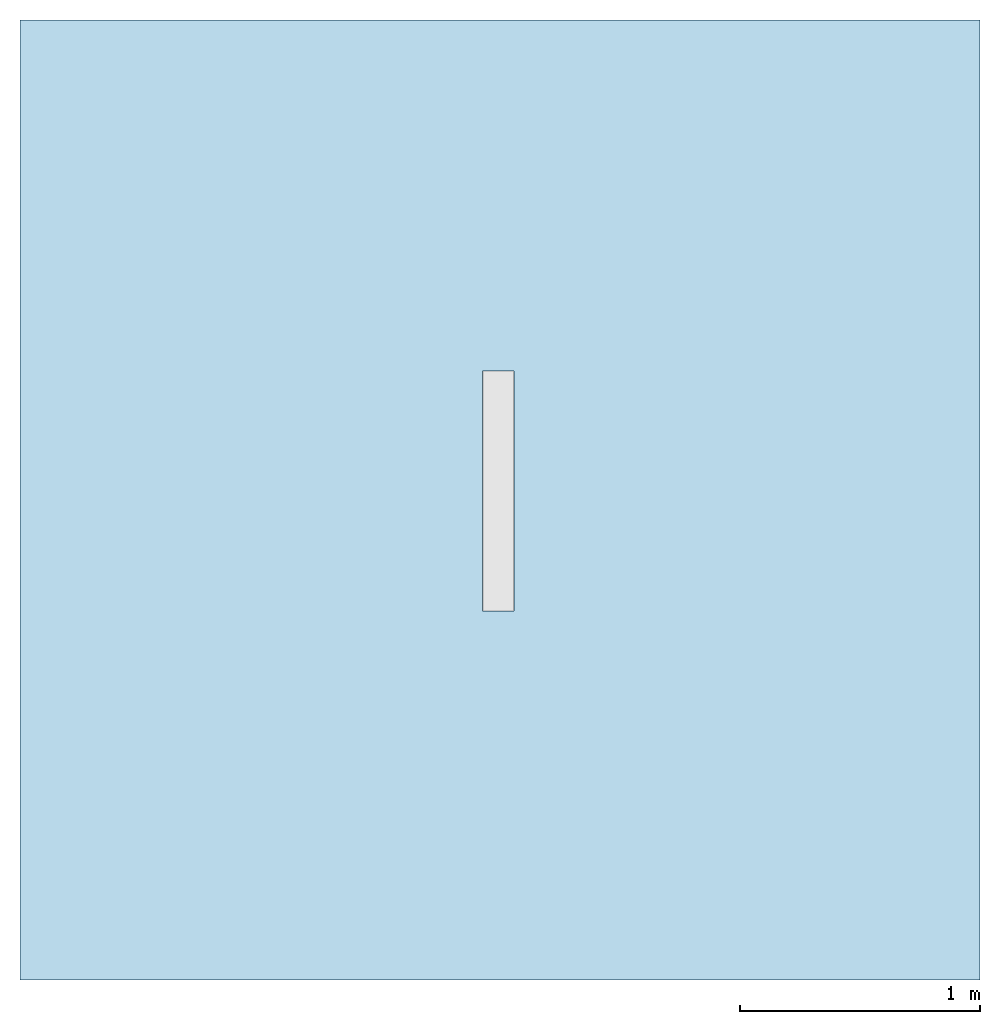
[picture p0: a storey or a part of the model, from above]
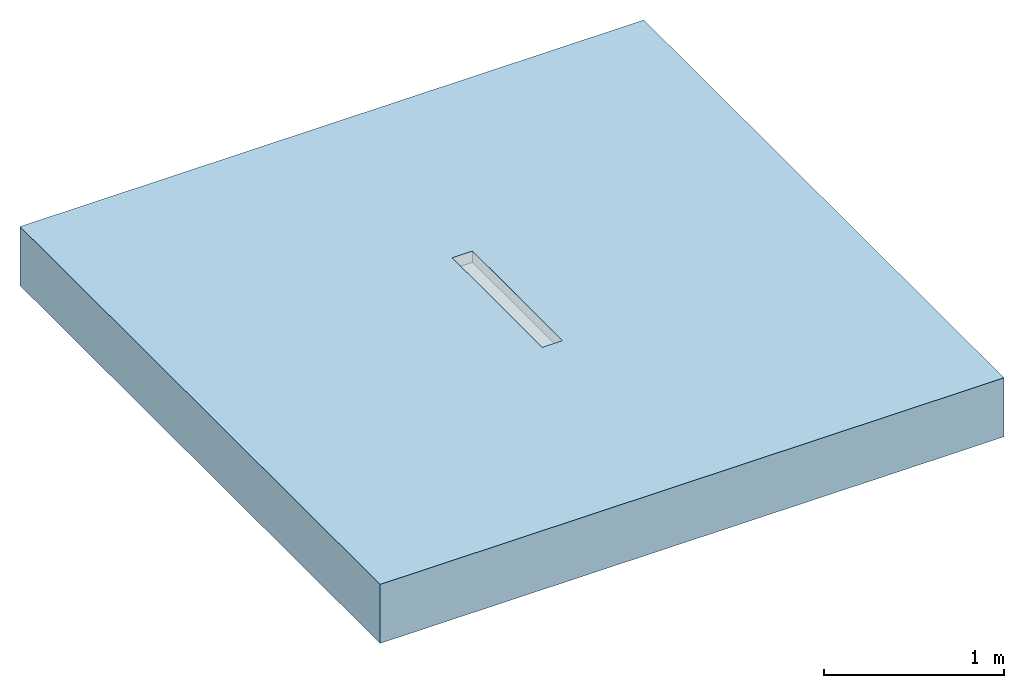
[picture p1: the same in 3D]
Properties of the parts of a building model (IFC2X3)

# File
Description: ViewDefinition [CoordinationView]
File name: Project Number
Time: 2014-06-06T15:01:31
Written by: The EXPRESS Data Manager Version 5.01.0100.02.64mod : 6 Jun 2012
Made in: 20130308_1515(x64) - Exporter 2014.0.2013.0308 - Default UI
Comment: STEP Physical File produced by: The EXPRESS Data Manager Version 5.01.0100.02.64mod : 6 Jun 2012 * Module: EDMstepFileFactory/EDMstandAlone * Creation date: Fri Jun 06 15:01:31 2014 * Host: IN-BLR-PC-0010 * Database: C:\Users\palleri\AppData\Local\Temp\{C48A4689-CF1B-40E8-B13B-AC1FC0C0441A}\ifc * Database version: 5507 * Database creation date: Fri Jun 06 15:01:29 2014 * Schema: IFC2X3 * Model: DataRepository.ifc * Model creation date: Fri Jun 06 15:01:30 2014 * Header model: DataRepository.ifc_HeaderModel * Header model creation date: Fri Jun 06 15:01:30 2014 * EDMuser: sdai-user * EDMgroup: sdai-group * License ID and type: 5605 : Permanent license. Expiry date: * EDMstepFileFactory options: 020000

# IfcProject, Project Number
LongName: Project Name; Phase: Project Status

# IfcSite, Default
RefLatitude: 42, 21, 30, 344238; RefLongitude: -71, -3, -35, -194702; RefElevation: 0 mm

# IfcBuilding
Pset_BuildingCommon - NumberOfStoreys: 1
Other - Client Name: Owner; Project Issue Date: Issue Date; Project Status: Project Status; Project Address: ## Street City, State Zip; Project Name: Project Name; Project Number: Project Number

# IfcBuildingStorey, Level 1
LongName: Level 1; Elevation: 0 mm
Graphics - Line Weight: 1; Line Pattern: Center; Symbol at End 1 Default: no; Symbol at End 2 Default: yes; Color: 0; Symbol: M_Level Head - Circle: M_Level Head - Circle
Constraints - Elevation Base: Project Base Point; Elevation: 0 mm
Identity Data - Name: Level 1; Building Story: yes; Structural: no
Dimensions - Computation Height: 0 mm

# IfcFlowTerminal: 36986 - Fixed Height Channel - Shallow Section - 1000mm LG - Invert Depth 75mm, ACO Freedeck Fixed Height Channel Intermediate Section Stainless Steel:36986 - Fixed Height Channel - Shallow Section - 1000mm LG - Invert Depth 75mm:322678
In: Level 1
Material: Stainless Steel Grade 304
Construction - End Plate Invert 1: no; 36954 - Grating - Plain Mesh - Stainless Steel 304 - 500mm long: no; End Plate Invert 2: no; 00272 - Grating - Slotted Grating - Stainless Steel 304 - 1000mm long: no; 36955 - Grating - Plain Mesh - Stainless Steel 304 - 1000mm long: yes; 00273 - Grating - Slotted Grating - Stainless Steel 304 - 500mm long: no
Phasing - Phase Created: New Construction
Identity Data - Mark: 29; Watermark1: This file is the property of ACO Technologies PLC; Manufacturer: ACO Building Drainage; E-mail Technical: abdtechnical@aco.co.uk; Fax: +44 (0)1462 851490; Watermark2: This file is water marked and users are prohibited to reproduce, adapt, distribute this information; Website: www.acobd.com; Watermarked By: www.acobd.com; Telephone: +44 (0)1462 816666; Watermarked With: BIM Manager Premium Suite; E-mail Sales: abdcommercial@aco.co.uk; Address: ACO Business Centre, Caxton Road, Bedford, MK41 0LF
Constraints - Level: Level: Level 1; Moves With Nearby Elements: no
Pset_ManufacturerTypeInformation - Manufacturer: ACO Building Drainage
General - Product Standard: BS EN 1433:2002, CE marked; Product Range: ACO Freedeck; Channel Recyclable: Fully recyclable; Product Description: ACO FreeDeck Fixed Height Channel - Intermediate Section; NBS Specification: NBS Section R10 Gravity Rainwater Drainage Systems, Subsection 365; Load Class: A15; Product Type: Linear Deck Drainage System; Channel Colour: Mid Grey; Maintenance Guidelines: X:\Electronic Literature\ABD Electronic Literature\Roof and Balcony Drainage\ACO Freedeck Brochure.pdf; Weight (Kg): 2.65kg; Dimensions (LxWxH): 1000 x 130 x 75; Installation Guidelines: X:\Electronic Literature\ABD Electronic Literature\Roof and Balcony Drainage\ACO Freedeck Brochure.pdf; Price: POA - contact ACO; Channel Material: Stainless Steel Grade 304; Channel Recycled Material Content: 60-70%; Product Code: 36986
Model Properties - End Plate Product Code 36988: End Plate - Stainless Steel for Invert Depth - 75mm - 0.07Kg; Grating Product Code 00273: Load Class A15 - Slotted Grating - 10 x 80mm Slot - Stainless Steel 304 - 500mm long - 1.0kg; Grating Product Code 36955: Load Class A15 - Mesh Grating - 14mm x 30mm Mesh - Stainless Steel 304 - 1000mm long - 3.0kg; Grating Product Code 00272: Load Class A15 - Slotted Grating - 10 x 80mm Slot - Stainless Steel 304 - 1000mm long - 2.2kg; Grating Product Code 36954: Load Class A15 - Mesh Grating - 14mm x 30mm Mesh - Stainless Steel 304 - 500mm long - 1.6kg
Other - Side Void: 4; Nos: 32
Dimensions - Channel End Length: -1000 mm; Grating End Length: 1000 mm; Height: 75 mm
Materials and Finishes - Material: Stainless Steel Grade 304

# IfcSlab: Floor:Generic Floor - 400mm, Floor:Generic Floor - 400mm:193825
In: Level 1
PredefinedType: FLOOR; Material: Concrete, Broom Finish 400 mm
Dimensions - Area: 16 m2; Thickness: 400 mm; Perimeter: 16000 mm; Volume: 6.39025 m3
Constraints - Height Offset From Level: 0 mm; Related to Mass: no; Room Bounding: yes; Level: Level: Level 1
Structural - Structural: no; Enable Analytical Model: no
Phasing - Phase Created: New Construction
Pset_SlabCommon - Reference: Generic Floor - 400mm; IsExternal: no; LoadBearing: yes; ThermalTransmittance: 2.615 kg/K/s3; PitchAngle: 0 deg
Analytical Properties - Heat Transfer Coefficient (U): 2.615; Roughness: 1; Absorptance: 0.1; Thermal Resistance (R): 0.382409; Thermal mass: 604440
Construction - Default Thickness: 400 mm; Function: Interior
Graphics - Coarse Scale Fill Color: 0
Materials and Finishes - Structural Material: Concrete, Broom Finish
